VERSION 5.7 ;
  NOWIREEXTENSIONATPIN ON ;
  DIVIDERCHAR "/" ;
  BUSBITCHARS "[]" ;
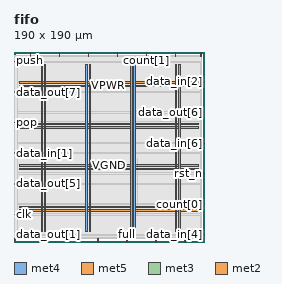
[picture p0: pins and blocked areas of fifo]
MACRO fifo
  CLASS BLOCK ;
  FOREIGN fifo ;
  ORIGIN 0.000 0.000 ;
  SIZE 190.000 BY 190.000 ;
  PIN VGND
    DIRECTION INOUT ;
    USE GROUND ;
    PORT
      LAYER met4 ;
        RECT 30.385 10.640 31.985 177.040 ;
    END
    PORT
      LAYER met4 ;
        RECT 75.120 10.640 76.720 177.040 ;
    END
    PORT
      LAYER met4 ;
        RECT 119.855 10.640 121.455 177.040 ;
    END
    PORT
      LAYER met4 ;
        RECT 164.590 10.640 166.190 177.040 ;
    END
    PORT
      LAYER met5 ;
        RECT 5.280 34.120 184.700 35.720 ;
    END
    PORT
      LAYER met5 ;
        RECT 5.280 75.600 184.700 77.200 ;
    END
    PORT
      LAYER met5 ;
        RECT 5.280 117.080 184.700 118.680 ;
    END
    PORT
      LAYER met5 ;
        RECT 5.280 158.560 184.700 160.160 ;
    END
  END VGND
  PIN VPWR
    DIRECTION INOUT ;
    USE POWER ;
    PORT
      LAYER met4 ;
        RECT 27.085 10.640 28.685 177.040 ;
    END
    PORT
      LAYER met4 ;
        RECT 71.820 10.640 73.420 177.040 ;
    END
    PORT
      LAYER met4 ;
        RECT 116.555 10.640 118.155 177.040 ;
    END
    PORT
      LAYER met4 ;
        RECT 161.290 10.640 162.890 177.040 ;
    END
    PORT
      LAYER met5 ;
        RECT 5.280 30.820 184.700 32.420 ;
    END
    PORT
      LAYER met5 ;
        RECT 5.280 72.300 184.700 73.900 ;
    END
    PORT
      LAYER met5 ;
        RECT 5.280 113.780 184.700 115.380 ;
    END
    PORT
      LAYER met5 ;
        RECT 5.280 155.260 184.700 156.860 ;
    END
  END VPWR
  PIN clk
    DIRECTION INPUT ;
    USE SIGNAL ;
    ANTENNAGATEAREA 1.286700 ;
    ANTENNADIFFAREA 0.434700 ;
    PORT
      LAYER met3 ;
        RECT 0.000 27.240 4.000 27.840 ;
    END
  END clk
  PIN count[0]
    DIRECTION OUTPUT TRISTATE ;
    USE SIGNAL ;
    ANTENNADIFFAREA 0.445500 ;
    PORT
      LAYER met3 ;
        RECT 186.000 37.440 190.000 38.040 ;
    END
  END count[0]
  PIN count[1]
    DIRECTION OUTPUT TRISTATE ;
    USE SIGNAL ;
    ANTENNADIFFAREA 0.795200 ;
    PORT
      LAYER met2 ;
        RECT 132.110 186.000 132.390 190.000 ;
    END
  END count[1]
  PIN count[2]
    DIRECTION OUTPUT TRISTATE ;
    USE SIGNAL ;
    ANTENNADIFFAREA 0.795200 ;
    PORT
      LAYER met2 ;
        RECT 45.170 186.000 45.450 190.000 ;
    END
  END count[2]
  PIN count[3]
    DIRECTION OUTPUT TRISTATE ;
    USE SIGNAL ;
    ANTENNADIFFAREA 0.795200 ;
    PORT
      LAYER met3 ;
        RECT 0.000 180.240 4.000 180.840 ;
    END
  END count[3]
  PIN data_in[0]
    DIRECTION INPUT ;
    USE SIGNAL ;
    ANTENNAGATEAREA 0.593700 ;
    ANTENNADIFFAREA 0.434700 ;
    PORT
      LAYER met2 ;
        RECT 186.850 186.000 187.130 190.000 ;
    END
  END data_in[0]
  PIN data_in[1]
    DIRECTION INPUT ;
    USE SIGNAL ;
    ANTENNAGATEAREA 0.593700 ;
    ANTENNADIFFAREA 0.434700 ;
    PORT
      LAYER met3 ;
        RECT 0.000 88.440 4.000 89.040 ;
    END
  END data_in[1]
  PIN data_in[2]
    DIRECTION INPUT ;
    USE SIGNAL ;
    ANTENNAGATEAREA 0.593700 ;
    ANTENNADIFFAREA 0.434700 ;
    PORT
      LAYER met3 ;
        RECT 186.000 159.840 190.000 160.440 ;
    END
  END data_in[2]
  PIN data_in[3]
    DIRECTION INPUT ;
    USE SIGNAL ;
    ANTENNAGATEAREA 0.593700 ;
    ANTENNADIFFAREA 0.434700 ;
    PORT
      LAYER met2 ;
        RECT 161.090 186.000 161.370 190.000 ;
    END
  END data_in[3]
  PIN data_in[4]
    DIRECTION INPUT ;
    USE SIGNAL ;
    ANTENNAGATEAREA 0.593700 ;
    ANTENNADIFFAREA 0.434700 ;
    PORT
      LAYER met2 ;
        RECT 170.750 0.000 171.030 4.000 ;
    END
  END data_in[4]
  PIN data_in[5]
    DIRECTION INPUT ;
    USE SIGNAL ;
    ANTENNAGATEAREA 0.593700 ;
    ANTENNADIFFAREA 0.434700 ;
    PORT
      LAYER met2 ;
        RECT 83.810 0.000 84.090 4.000 ;
    END
  END data_in[5]
  PIN data_in[6]
    DIRECTION INPUT ;
    USE SIGNAL ;
    ANTENNAGATEAREA 0.647700 ;
    ANTENNADIFFAREA 0.434700 ;
    PORT
      LAYER met3 ;
        RECT 186.000 98.640 190.000 99.240 ;
    END
  END data_in[6]
  PIN data_in[7]
    DIRECTION INPUT ;
    USE SIGNAL ;
    ANTENNAGATEAREA 0.647700 ;
    ANTENNADIFFAREA 0.434700 ;
    PORT
      LAYER met2 ;
        RECT 141.770 0.000 142.050 4.000 ;
    END
  END data_in[7]
  PIN data_out[0]
    DIRECTION OUTPUT TRISTATE ;
    USE SIGNAL ;
    ANTENNADIFFAREA 0.795200 ;
    PORT
      LAYER met2 ;
        RECT 0.090 0.000 0.370 4.000 ;
    END
  END data_out[0]
  PIN data_out[1]
    DIRECTION OUTPUT TRISTATE ;
    USE SIGNAL ;
    ANTENNADIFFAREA 0.795200 ;
    PORT
      LAYER met2 ;
        RECT 25.850 0.000 26.130 4.000 ;
    END
  END data_out[1]
  PIN data_out[2]
    DIRECTION OUTPUT TRISTATE ;
    USE SIGNAL ;
    ANTENNADIFFAREA 0.795200 ;
    PORT
      LAYER met2 ;
        RECT 74.150 186.000 74.430 190.000 ;
    END
  END data_out[2]
  PIN data_out[3]
    DIRECTION OUTPUT TRISTATE ;
    USE SIGNAL ;
    ANTENNADIFFAREA 0.445500 ;
    PORT
      LAYER met3 ;
        RECT 186.000 6.840 190.000 7.440 ;
    END
  END data_out[3]
  PIN data_out[4]
    DIRECTION OUTPUT TRISTATE ;
    USE SIGNAL ;
    ANTENNADIFFAREA 0.795200 ;
    PORT
      LAYER met2 ;
        RECT 54.830 0.000 55.110 4.000 ;
    END
  END data_out[4]
  PIN data_out[5]
    DIRECTION OUTPUT TRISTATE ;
    USE SIGNAL ;
    ANTENNADIFFAREA 0.795200 ;
    PORT
      LAYER met3 ;
        RECT 0.000 57.840 4.000 58.440 ;
    END
  END data_out[5]
  PIN data_out[6]
    DIRECTION OUTPUT TRISTATE ;
    USE SIGNAL ;
    ANTENNADIFFAREA 0.795200 ;
    PORT
      LAYER met3 ;
        RECT 186.000 129.240 190.000 129.840 ;
    END
  END data_out[6]
  PIN data_out[7]
    DIRECTION OUTPUT TRISTATE ;
    USE SIGNAL ;
    ANTENNADIFFAREA 0.795200 ;
    PORT
      LAYER met3 ;
        RECT 0.000 149.640 4.000 150.240 ;
    END
  END data_out[7]
  PIN empty
    DIRECTION OUTPUT TRISTATE ;
    USE SIGNAL ;
    ANTENNADIFFAREA 0.795200 ;
    PORT
      LAYER met2 ;
        RECT 103.130 186.000 103.410 190.000 ;
    END
  END empty
  PIN full
    DIRECTION OUTPUT TRISTATE ;
    USE SIGNAL ;
    ANTENNADIFFAREA 0.795200 ;
    PORT
      LAYER met2 ;
        RECT 112.790 0.000 113.070 4.000 ;
    END
  END full
  PIN pop
    DIRECTION INPUT ;
    USE SIGNAL ;
    ANTENNAGATEAREA 0.647700 ;
    ANTENNADIFFAREA 0.434700 ;
    PORT
      LAYER met3 ;
        RECT 0.000 119.040 4.000 119.640 ;
    END
  END pop
  PIN push
    DIRECTION INPUT ;
    USE SIGNAL ;
    ANTENNAGATEAREA 0.593700 ;
    ANTENNADIFFAREA 0.434700 ;
    PORT
      LAYER met2 ;
        RECT 16.190 186.000 16.470 190.000 ;
    END
  END push
  PIN rst_n
    DIRECTION INPUT ;
    USE SIGNAL ;
    ANTENNAGATEAREA 0.631200 ;
    ANTENNADIFFAREA 0.434700 ;
    PORT
      LAYER met3 ;
        RECT 186.000 68.040 190.000 68.640 ;
    END
  END rst_n
  OBS
      LAYER li1 ;
        RECT 5.520 10.795 184.460 176.885 ;
      LAYER met1 ;
        RECT 0.070 10.640 187.150 177.040 ;
      LAYER met2 ;
        RECT 0.100 185.720 15.910 186.730 ;
        RECT 16.750 185.720 44.890 186.730 ;
        RECT 45.730 185.720 73.870 186.730 ;
        RECT 74.710 185.720 102.850 186.730 ;
        RECT 103.690 185.720 131.830 186.730 ;
        RECT 132.670 185.720 160.810 186.730 ;
        RECT 161.650 185.720 186.570 186.730 ;
        RECT 0.100 4.280 187.120 185.720 ;
        RECT 0.650 4.000 25.570 4.280 ;
        RECT 26.410 4.000 54.550 4.280 ;
        RECT 55.390 4.000 83.530 4.280 ;
        RECT 84.370 4.000 112.510 4.280 ;
        RECT 113.350 4.000 141.490 4.280 ;
        RECT 142.330 4.000 170.470 4.280 ;
        RECT 171.310 4.000 187.120 4.280 ;
      LAYER met3 ;
        RECT 4.400 179.840 186.000 180.690 ;
        RECT 3.990 160.840 186.000 179.840 ;
        RECT 3.990 159.440 185.600 160.840 ;
        RECT 3.990 150.640 186.000 159.440 ;
        RECT 4.400 149.240 186.000 150.640 ;
        RECT 3.990 130.240 186.000 149.240 ;
        RECT 3.990 128.840 185.600 130.240 ;
        RECT 3.990 120.040 186.000 128.840 ;
        RECT 4.400 118.640 186.000 120.040 ;
        RECT 3.990 99.640 186.000 118.640 ;
        RECT 3.990 98.240 185.600 99.640 ;
        RECT 3.990 89.440 186.000 98.240 ;
        RECT 4.400 88.040 186.000 89.440 ;
        RECT 3.990 69.040 186.000 88.040 ;
        RECT 3.990 67.640 185.600 69.040 ;
        RECT 3.990 58.840 186.000 67.640 ;
        RECT 4.400 57.440 186.000 58.840 ;
        RECT 3.990 38.440 186.000 57.440 ;
        RECT 3.990 37.040 185.600 38.440 ;
        RECT 3.990 28.240 186.000 37.040 ;
        RECT 4.400 26.840 186.000 28.240 ;
        RECT 3.990 7.840 186.000 26.840 ;
        RECT 3.990 6.975 185.600 7.840 ;
      LAYER met4 ;
        RECT 123.575 26.015 123.905 83.465 ;
  END
END fifo
END LIBRARY

